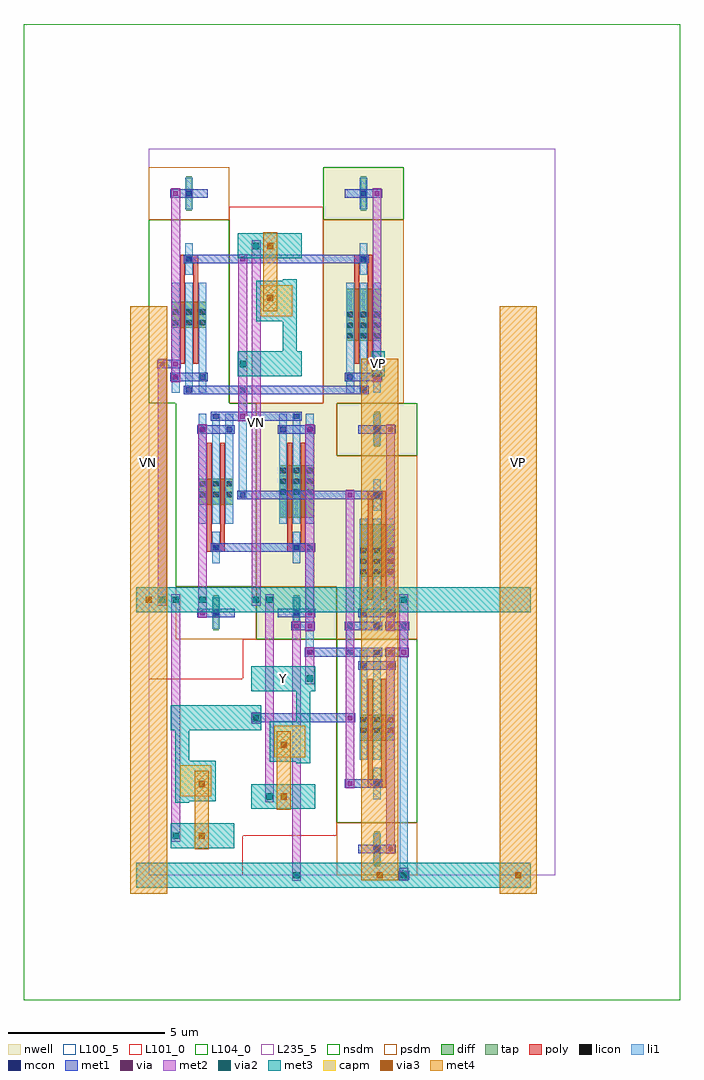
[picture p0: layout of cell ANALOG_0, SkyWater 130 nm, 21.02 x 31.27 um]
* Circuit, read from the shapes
.subckt ANALOG_0 VN VP Y
XM1 n1 n2 VN VN sky130_fd_pr__nfet_01v8 w=0.84 l=0.15 m=2
XM2 n2 Y VN VN sky130_fd_pr__nfet_01v8 w=0.84 l=0.15 m=2
XM3 Y n1 VN VN sky130_fd_pr__nfet_01v8 w=0.84 l=0.15 m=2
XM4 n2 Y VP VP sky130_fd_pr__pfet_01v8 w=1.68 l=0.15 m=2
XM5 n1 n2 VP VP sky130_fd_pr__pfet_01v8 w=1.68 l=0.15 m=2
XM6 Y n1 VP VP sky130_fd_pr__pfet_01v8 w=1.68 l=0.15 m=2
XC7 VN n1 sky130_fd_pr__cap_mim_m3_1 w=1 l=1
XC8 VN n2 sky130_fd_pr__cap_mim_m3_1 w=1 l=1
XC9 VN Y sky130_fd_pr__cap_mim_m3_1 w=1 l=1
.ends

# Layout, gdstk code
from math import pi, radians
import gdstk
lib = gdstk.Library(unit=1e-6, precision=1e-09)
def R(c, l, rs):  # rectangles x0, y0, x1, y1
    for r in rs: c.add(gdstk.rectangle(r[:2], r[2:], *l))
def A(c, l, x, y, w, h, nx, ny, dx, dy):  # array of equal rectangles
    R(c, l, [(x+i*dx, y+j*dy, x+i*dx+w, y+j*dy+h) for i in range(nx) for j in range(ny)])
def P(c, l, *ps):  # polygons
    for p in ps: c.add(gdstk.Polygon(p, *l))
nwell = (64, 20)
diff = (65, 20)
tap = (65, 44)
poly = (66, 20)
licon = (66, 44)
li1 = (67, 20)
mcon = (67, 44)
met1 = (68, 20)
via = (68, 44)
met2 = (69, 20)
via2 = (69, 44)
met3 = (70, 20)
via3 = (70, 44)
met4 = (71, 20)
capm = (89, 44)
nsdm = (93, 44)
psdm = (94, 20)
L100_5 = (100, 5)
L101_0 = (101, 0)
L104_0 = (104, 0)
L235_5 = (235, 5)

nmos_s_25628869_x1_y1_16 = lib.new_cell('NMOS_S_25628869_X1_Y1_1677518466_1677518466')
R(nmos_s_25628869_x1_y1_16, diff, [(0.735,2.415,1.845,3.255)])
R(nmos_s_25628869_x1_y1_16, tap, [(1.205,6.16,1.375,7.28)])
R(nmos_s_25628869_x1_y1_16, poly, [(1,1.26,1.15,4.62), (1.43,1.26,1.58,4.62), (1,4.485,1.58,4.755)])
A(nmos_s_25628869_x1_y1_16, licon, 0.775, 2.495, 0.17, 0.17, 3, 2, 0.43, 0.34)
R(nmos_s_25628869_x1_y1_16, licon, [(1.205,4.535,1.375,4.705), (1.205,6.635,1.375,6.805)])
A(nmos_s_25628869_x1_y1_16, li1, 0.735, 0.335, 0.25, 3.53, 3, 1, 0.43, 0)
R(nmos_s_25628869_x1_y1_16, li1, [(1.165,4.115,1.415,5.125), (1.165,6.215,1.415,7.225)])
R(nmos_s_25628869_x1_y1_16, mcon, [(1.205,0.335,1.375,0.505), (0.775,0.755,0.945,0.925), (1.635,0.755,1.805,0.925), (1.205,4.535,1.375,4.705), (1.205,6.635,1.375,6.805)])
R(nmos_s_25628869_x1_y1_16, met1, [(0.26,0.28,1.46,0.56), (0.69,0.7,1.89,0.98), (0.26,4.48,1.46,4.76), (0.69,6.58,1.89,6.86)])
R(nmos_s_25628869_x1_y1_16, via, [(1.645,0.765,1.795,0.915), (1.645,6.645,1.795,6.795)])
R(nmos_s_25628869_x1_y1_16, met2, [(1.58,0.68,1.86,6.88)])
R(nmos_s_25628869_x1_y1_16, nsdm, [(0,0,2.58,5.88)])
R(nmos_s_25628869_x1_y1_16, psdm, [(0,5.88,2.58,7.56)])
R(nmos_s_25628869_x1_y1_16, L100_5, [(0,0,2.58,7.56)])

pmos_s_89421238_x1_y1_16 = lib.new_cell('PMOS_S_89421238_X1_Y1_1677518467_1677518466')
R(pmos_s_89421238_x1_y1_16, nwell, [(0,0,2.58,7.56)])
R(pmos_s_89421238_x1_y1_16, diff, [(0.735,1.995,1.845,3.675)])
R(pmos_s_89421238_x1_y1_16, tap, [(1.205,6.16,1.375,7.28)])
R(pmos_s_89421238_x1_y1_16, poly, [(1,1.26,1.15,4.62), (1.43,1.26,1.58,4.62), (1,4.485,1.58,4.755)])
A(pmos_s_89421238_x1_y1_16, licon, 0.775, 2.075, 0.17, 0.17, 3, 3, 0.43, 0.34)
R(pmos_s_89421238_x1_y1_16, licon, [(1.205,4.535,1.375,4.705), (1.205,6.635,1.375,6.805)])
A(pmos_s_89421238_x1_y1_16, li1, 0.735, 0.335, 0.25, 3.53, 3, 1, 0.43, 0)
R(pmos_s_89421238_x1_y1_16, li1, [(1.165,4.115,1.415,5.125), (1.165,6.215,1.415,7.225)])
R(pmos_s_89421238_x1_y1_16, mcon, [(1.205,0.335,1.375,0.505), (0.775,0.755,0.945,0.925), (1.635,0.755,1.805,0.925), (1.205,4.535,1.375,4.705), (1.205,6.635,1.375,6.805)])
R(pmos_s_89421238_x1_y1_16, met1, [(0.26,0.28,1.46,0.56), (0.69,0.7,1.89,0.98), (0.26,4.48,1.46,4.76), (0.69,6.58,1.89,6.86)])
R(pmos_s_89421238_x1_y1_16, via, [(1.645,0.765,1.795,0.915), (1.645,6.645,1.795,6.795)])
R(pmos_s_89421238_x1_y1_16, met2, [(1.58,0.68,1.86,6.88)])
R(pmos_s_89421238_x1_y1_16, nsdm, [(0,5.88,2.58,7.56)])
R(pmos_s_89421238_x1_y1_16, psdm, [(0,0,2.58,5.88)])
R(pmos_s_89421238_x1_y1_16, L100_5, [(0,0,2.58,7.56)])

inv_21850877_pg0_0_0_167 = lib.new_cell('INV_21850877_PG0_0_0_1677518466')
R(inv_21850877_pg0_0_0_167, li1, [(0.305,7.055,0.555,7.225), (0.305,7.055,0.555,7.225), (0.305,7.14,0.555,7.98), (0.305,7.895,0.555,8.065), (0.305,7.895,0.555,8.065)])
R(inv_21850877_pg0_0_0_167, mcon, [(0.345,7.055,0.515,7.225), (0.345,7.055,0.515,7.225), (0.345,7.895,0.515,8.065), (0.345,7.895,0.515,8.065)])
R(inv_21850877_pg0_0_0_167, met1, [(0.27,2.8,0.59,3.08), (0.27,2.8,0.59,3.08), (0.26,7,0.6,7.28), (0.26,7,0.6,7.28), (0.26,7.84,0.6,8.12), (0.26,7.84,0.6,8.12), (0.27,12.04,0.59,12.32), (0.27,12.04,0.59,12.32)])
P(inv_21850877_pg0_0_0_167, met1, [(0,0),(0,0),(0,0),(0,0)],
  [(0,0),(0,0),(0,0),(0,0)],
  [(0,0),(0,0),(0,0),(0,0)],
  [(0,0),(0,0),(0,0),(0,0)])
R(inv_21850877_pg0_0_0_167, via, [(0.355,2.865,0.505,3.015), (0.355,2.865,0.505,3.015), (0.355,12.105,0.505,12.255), (0.355,12.105,0.505,12.255)])
R(inv_21850877_pg0_0_0_167, met2, [(0.29,2.78,0.57,3.1), (0.29,2.78,0.57,3.1), (0.29,2.94,0.57,12.18), (0.29,12.02,0.57,12.34), (0.29,12.02,0.57,12.34)])
P(inv_21850877_pg0_0_0_167, met2, [(0,0),(0,0),(0,0),(0,0)],
  [(0,0),(0,0),(0,0),(0,0)])
R(inv_21850877_pg0_0_0_167, L235_5, [(0,0,2.58,15.12)])
inv_21850877_pg0_0_0_167.add(gdstk.Reference(nmos_s_25628869_x1_y1_16, (0,7.56), x_reflection=True))
inv_21850877_pg0_0_0_167.add(gdstk.Reference(pmos_s_89421238_x1_y1_16, (0,7.56)))

cap_2t_9576091_167751846 = lib.new_cell('CAP_2T_9576091_1677518467')
R(cap_2t_9576091_167751846, met3, [(0.265,0.86,2.315,1.66), (1.71,2.32,2.16,4.84), (0.86,2.37,2.16,3.67), (0.265,4.64,2.315,5.44)])
R(cap_2t_9576091_167751846, via3, [(1.21,1.16,1.41,1.36), (1.21,2.82,1.41,3.02)])
R(cap_2t_9576091_167751846, met4, [(1.085,0.83,1.535,3.35)])
R(cap_2t_9576091_167751846, capm, [(1.01,2.52,2.01,3.52)])
R(cap_2t_9576091_167751846, L100_5, [(0,0,3.01,6.3)])
R(cap_2t_9576091_167751846, L101_0, [(0,0,3.01,6.3)])

c_nmos_s_25628869_x1_y1_16 = lib.new_cell('NMOS_S_25628869_X1_Y1_1677518468')
R(c_nmos_s_25628869_x1_y1_16, diff, [(0.735,2.415,1.845,3.255)])
R(c_nmos_s_25628869_x1_y1_16, tap, [(1.205,6.16,1.375,7.28)])
R(c_nmos_s_25628869_x1_y1_16, poly, [(1,1.26,1.15,4.62), (1.43,1.26,1.58,4.62), (1,4.485,1.58,4.755)])
A(c_nmos_s_25628869_x1_y1_16, licon, 0.775, 2.495, 0.17, 0.17, 3, 2, 0.43, 0.34)
R(c_nmos_s_25628869_x1_y1_16, licon, [(1.205,4.535,1.375,4.705), (1.205,6.635,1.375,6.805)])
A(c_nmos_s_25628869_x1_y1_16, li1, 0.735, 0.335, 0.25, 3.53, 3, 1, 0.43, 0)
R(c_nmos_s_25628869_x1_y1_16, li1, [(1.165,4.115,1.415,5.125), (1.165,6.215,1.415,7.225)])
R(c_nmos_s_25628869_x1_y1_16, mcon, [(1.205,0.335,1.375,0.505), (0.775,0.755,0.945,0.925), (1.635,0.755,1.805,0.925), (1.205,4.535,1.375,4.705), (1.205,6.635,1.375,6.805)])
R(c_nmos_s_25628869_x1_y1_16, met1, [(0.26,0.28,1.46,0.56), (0.69,0.7,1.89,0.98), (0.26,4.48,1.46,4.76), (0.69,6.58,1.89,6.86)])
R(c_nmos_s_25628869_x1_y1_16, via, [(1.645,0.765,1.795,0.915), (1.645,6.645,1.795,6.795)])
R(c_nmos_s_25628869_x1_y1_16, met2, [(1.58,0.68,1.86,6.88)])
R(c_nmos_s_25628869_x1_y1_16, nsdm, [(0,0,2.58,5.88)])
R(c_nmos_s_25628869_x1_y1_16, psdm, [(0,5.88,2.58,7.56)])
R(c_nmos_s_25628869_x1_y1_16, L100_5, [(0,0,2.58,7.56)])

c_pmos_s_89421238_x1_y1_16 = lib.new_cell('PMOS_S_89421238_X1_Y1_1677518469')
R(c_pmos_s_89421238_x1_y1_16, nwell, [(0,0,2.58,7.56)])
R(c_pmos_s_89421238_x1_y1_16, diff, [(0.735,1.995,1.845,3.675)])
R(c_pmos_s_89421238_x1_y1_16, tap, [(1.205,6.16,1.375,7.28)])
R(c_pmos_s_89421238_x1_y1_16, poly, [(1,1.26,1.15,4.62), (1.43,1.26,1.58,4.62), (1,4.485,1.58,4.755)])
A(c_pmos_s_89421238_x1_y1_16, licon, 0.775, 2.075, 0.17, 0.17, 3, 3, 0.43, 0.34)
R(c_pmos_s_89421238_x1_y1_16, licon, [(1.205,4.535,1.375,4.705), (1.205,6.635,1.375,6.805)])
A(c_pmos_s_89421238_x1_y1_16, li1, 0.735, 0.335, 0.25, 3.53, 3, 1, 0.43, 0)
R(c_pmos_s_89421238_x1_y1_16, li1, [(1.165,4.115,1.415,5.125), (1.165,6.215,1.415,7.225)])
R(c_pmos_s_89421238_x1_y1_16, mcon, [(1.205,0.335,1.375,0.505), (0.775,0.755,0.945,0.925), (1.635,0.755,1.805,0.925), (1.205,4.535,1.375,4.705), (1.205,6.635,1.375,6.805)])
R(c_pmos_s_89421238_x1_y1_16, met1, [(0.26,0.28,1.46,0.56), (0.69,0.7,1.89,0.98), (0.26,4.48,1.46,4.76), (0.69,6.58,1.89,6.86)])
R(c_pmos_s_89421238_x1_y1_16, via, [(1.645,0.765,1.795,0.915), (1.645,6.645,1.795,6.795)])
R(c_pmos_s_89421238_x1_y1_16, met2, [(1.58,0.68,1.86,6.88)])
R(c_pmos_s_89421238_x1_y1_16, nsdm, [(0,5.88,2.58,7.56)])
R(c_pmos_s_89421238_x1_y1_16, psdm, [(0,0,2.58,5.88)])
R(c_pmos_s_89421238_x1_y1_16, L100_5, [(0,0,2.58,7.56)])

analog_0 = lib.new_cell('ANALOG_0')
R(analog_0, li1, [(8.045,-0.085,8.295,0.085), (8.045,0,8.295,7.98), (5.035,7.055,5.285,7.225), (5.035,7.055,5.285,7.225), (5.035,7.055,5.285,7.225), (5.035,7.055,5.285,7.225), (5.035,7.14,5.285,10.5), (8.045,7.895,8.295,8.065), (8.045,7.895,8.295,8.065), (5.035,10.415,5.285,10.585), (5.035,10.415,5.285,10.585), (5.035,10.415,5.285,10.585), (5.035,10.415,5.285,10.585), (2.885,12.095,3.135,12.265), (2.885,12.095,3.135,12.265), (2.885,12.095,3.135,12.265), (2.885,12.095,3.135,12.265), (2.885,12.18,3.135,15.54), (2.885,15.455,3.135,15.625), (2.885,15.455,3.135,15.625), (2.885,15.455,3.135,15.625), (2.885,15.455,3.135,15.625)])
P(analog_0, li1, [(0,0),(0,0),(0,0),(0,0)])
R(analog_0, mcon, [(8.085,-0.085,8.255,0.085), (5.075,7.055,5.245,7.225), (5.075,7.055,5.245,7.225), (5.075,7.055,5.245,7.225), (5.075,7.055,5.245,7.225), (8.085,7.895,8.255,8.065), (8.085,7.895,8.255,8.065), (5.075,10.415,5.245,10.585), (5.075,10.415,5.245,10.585), (5.075,10.415,5.245,10.585), (5.075,10.415,5.245,10.585), (2.925,12.095,3.095,12.265), (2.925,12.095,3.095,12.265), (2.925,12.095,3.095,12.265), (2.925,12.095,3.095,12.265), (2.925,15.455,3.095,15.625), (2.925,15.455,3.095,15.625), (2.925,15.455,3.095,15.625), (2.925,15.455,3.095,15.625)])
R(analog_0, met1, [(8,-0.14,8.34,0.14), (8.01,-0.14,8.33,0.14), (8.021,-0.14,8.319,0.14), (3.28,4.9,3.6,5.18), (3.44,4.9,6.45,5.18), (6.29,4.9,6.61,5.18), (6.29,4.9,6.61,5.18), (6.29,4.9,6.61,5.18), (6.29,4.9,6.61,5.18), (6.29,4.9,6.61,5.18), (6.29,4.9,6.61,5.18), (4.99,7,5.33,7.28), (4.99,7,5.33,7.28), (4.99,7,5.33,7.28), (4.99,7,5.33,7.28), (5,7,5.32,7.28), (5,7,5.32,7.28), (5,7,5.32,7.28), (5,7,5.32,7.28), (5,7,5.32,7.28), (5,7,5.32,7.28), (5.16,7,6.45,7.28), (7.58,7,7.9,7.28), (7.58,7,7.9,7.28), (7.74,7,8.17,7.28), (8.01,7,8.33,7.28), (8.01,7,8.33,7.28), (4.57,7.84,4.89,8.12), (4.57,7.84,4.89,8.12), (4.57,7.84,4.89,8.12), (4.73,7.84,5.16,8.12), (5,7.84,5.32,8.12), (5,7.84,5.32,8.12), (5,7.84,5.32,8.12), (7.58,7.84,7.9,8.12), (7.58,7.84,7.9,8.12), (7.74,7.84,8.17,8.12), (8,7.84,8.34,8.12), (8,7.84,8.34,8.12), (3.01,10.36,3.87,10.64), (4.73,10.36,5.16,10.64), (4.99,10.36,5.33,10.64), (4.99,10.36,5.33,10.64), (4.99,10.36,5.33,10.64), (4.99,10.36,5.33,10.64), (2.84,12.04,3.18,12.32), (2.84,12.04,3.18,12.32), (2.84,12.04,3.18,12.32), (2.84,12.04,3.18,12.32), (3.01,12.04,6.45,12.32), (2.85,14.56,3.17,14.84), (2.85,14.56,3.17,14.84), (2.85,14.56,3.17,14.84), (2.85,14.56,3.17,14.84), (2.85,14.56,3.17,14.84), (2.85,14.56,3.17,14.84), (3.01,14.56,3.87,14.84), (2.15,15.4,3.01,15.68), (2.84,15.4,3.18,15.68), (2.84,15.4,3.18,15.68), (2.84,15.4,3.18,15.68), (2.84,15.4,3.18,15.68), (3.01,15.4,6.02,15.68), (0.27,16.24,0.59,16.52), (0.27,16.24,0.59,16.52), (0.27,16.24,0.59,16.52), (0.43,16.24,0.86,16.52), (0.7,16.24,1.02,16.52), (0.7,16.24,1.02,16.52), (0.7,16.24,1.02,16.52), (2.15,19.6,3.01,19.88), (2.85,19.6,3.17,19.88), (2.85,19.6,3.17,19.88), (2.85,19.6,3.17,19.88), (2.85,19.6,3.17,19.88), (3.01,19.6,6.02,19.88)])
P(analog_0, met1, [(0,0),(0,0),(0,0),(0,0)],
  [(0,0),(0,0),(0,0),(0,0)],
  [(0,0),(0,0),(0,0),(0,0)],
  [(0,0),(0,0),(0,0),(0,0)],
  [(0,0),(0,0),(0,0),(0,0)],
  [(0,0),(0,0),(0,0),(0,0)],
  [(0,0),(0,0),(0,0),(0,0)],
  [(0,0),(0,0),(0,0),(0,0)],
  [(0,0),(0,0),(0,0),(0,0)],
  [(0,0),(0,0),(0,0),(0,0)],
  [(0,0),(0,0),(0,0),(0,0)],
  [(0,0),(0,0),(0,0),(0,0)],
  [(0,0),(0,0),(0,0),(0,0)],
  [(0,0),(0,0),(0,0),(0,0)],
  [(0,0),(0,0),(0,0),(0,0)],
  [(0,0),(0,0),(0,0),(0,0)])
R(analog_0, via, [(8.095,-0.075,8.245,0.075), (3.365,4.965,3.515,5.115), (6.375,4.965,6.525,5.115), (6.375,4.965,6.525,5.115), (6.375,4.965,6.525,5.115), (6.375,4.965,6.525,5.115), (6.375,4.965,6.525,5.115), (6.375,4.965,6.525,5.115), (5.085,7.065,5.235,7.215), (5.085,7.065,5.235,7.215), (5.085,7.065,5.235,7.215), (5.085,7.065,5.235,7.215), (5.085,7.065,5.235,7.215), (5.085,7.065,5.235,7.215), (7.665,7.065,7.815,7.215), (7.665,7.065,7.815,7.215), (8.095,7.065,8.245,7.215), (8.095,7.065,8.245,7.215), (4.655,7.905,4.805,8.055), (4.655,7.905,4.805,8.055), (4.655,7.905,4.805,8.055), (5.085,7.905,5.235,8.055), (5.085,7.905,5.235,8.055), (5.085,7.905,5.235,8.055), (7.665,7.905,7.815,8.055), (7.665,7.905,7.815,8.055), (2.935,14.625,3.085,14.775), (2.935,14.625,3.085,14.775), (2.935,14.625,3.085,14.775), (2.935,14.625,3.085,14.775), (2.935,14.625,3.085,14.775), (2.935,14.625,3.085,14.775), (0.355,16.305,0.505,16.455), (0.355,16.305,0.505,16.455), (0.355,16.305,0.505,16.455), (0.785,16.305,0.935,16.455), (0.785,16.305,0.935,16.455), (0.785,16.305,0.935,16.455), (2.935,19.665,3.085,19.815), (2.935,19.665,3.085,19.815), (2.935,19.665,3.085,19.815), (2.935,19.665,3.085,19.815)])
R(analog_0, met2, [(4.59,-0.185,4.87,0.185), (4.59,-0.185,4.87,0.185), (4.59,-0.185,4.87,0.185), (8.03,-0.185,8.31,0.185), (8.03,-0.185,8.31,0.185), (8.03,-0.16,8.31,0.16), (4.59,0,4.87,7.98), (8.03,0,8.31,0.242), (0.72,1.075,1,1.445), (0.72,1.075,1,1.445), (0.72,1.075,1,1.445), (0.72,1.075,1,1.445), (0.72,1.075,1,1.445), (0.72,1.075,1,1.445), (0.72,1.26,1,8.82), (3.73,2.335,4.01,2.705), (3.73,2.335,4.01,2.705), (3.73,2.335,4.01,2.705), (3.73,2.335,4.01,2.705), (3.73,2.335,4.01,2.705), (3.73,2.52,4.01,8.82), (3.3,4.855,3.58,5.225), (3.3,4.88,3.58,5.2), (6.31,4.88,6.59,5.2), (6.31,4.88,6.59,5.2), (6.31,4.88,6.59,5.2), (6.31,4.88,6.59,5.2), (6.31,4.88,6.59,5.2), (6.31,4.88,6.59,5.2), (3.3,4.919,3.58,5.161), (5.02,6.115,5.3,6.485), (5.02,6.115,5.3,6.485), (5.02,6.115,5.3,6.485), (5.02,6.115,5.3,6.485), (5.02,6.115,5.3,6.485), (5.02,6.115,5.3,6.485), (5.02,6.3,5.3,7.14), (7.6,6.72,7.88,7.14), (5.02,6.98,5.3,7.3), (5.02,6.98,5.3,7.3), (5.02,6.98,5.3,7.3), (5.02,6.98,5.3,7.3), (5.02,6.98,5.3,7.3), (5.02,6.98,5.3,7.3), (7.6,6.98,7.88,7.3), (7.6,6.98,7.88,7.3), (8.03,6.98,8.31,7.3), (8.03,6.98,8.31,7.3), (8.03,7.14,8.31,8.82), (4.59,7.82,4.87,8.14), (4.59,7.82,4.87,8.14), (4.59,7.82,4.87,8.14), (5.02,7.82,5.3,8.14), (5.02,7.82,5.3,8.14), (5.02,7.82,5.3,8.14), (7.6,7.82,7.88,8.14), (7.6,7.82,7.88,8.14), (5.02,7.98,5.3,8.4), (7.6,7.98,7.88,8.4), (0.29,8.635,0.57,9.005), (0.29,8.635,0.57,9.005), (0.29,8.635,0.57,9.005), (0.72,8.635,1,9.005), (0.72,8.635,1,9.005), (0.72,8.635,1,9.005), (0.72,8.635,1,9.005), (0.72,8.635,1,9.005), (0.72,8.635,1,9.005), (1.58,8.635,1.86,9.005), (1.58,8.635,1.86,9.005), (1.58,8.635,1.86,9.005), (1.58,8.635,1.86,9.005), (3.3,8.635,3.58,9.005), (3.3,8.635,3.58,9.005), (3.3,8.635,3.58,9.005), (3.3,8.635,3.58,9.005), (3.3,8.635,3.58,9.005), (3.3,8.635,3.58,9.005), (3.3,8.635,3.58,9.005), (3.73,8.635,4.01,9.005), (3.73,8.635,4.01,9.005), (3.73,8.635,4.01,9.005), (3.73,8.635,4.01,9.005), (3.73,8.635,4.01,9.005), (8.03,8.635,8.31,9.005), (8.03,8.635,8.31,9.005), (0.29,8.82,0.57,16.38), (3.3,8.82,3.58,20.16), (2.87,14.54,3.15,14.86), (2.87,14.54,3.15,14.86), (2.87,14.54,3.15,14.86), (2.87,14.54,3.15,14.86), (2.87,14.54,3.15,14.86), (2.87,14.54,3.15,14.86), (2.87,14.7,3.15,16.38), (2.87,16.195,3.15,16.565), (2.87,16.195,3.15,16.565), (2.87,16.195,3.15,16.565), (2.87,16.195,3.15,16.565), (2.87,16.195,3.15,16.565), (2.87,16.195,3.15,16.565), (7.17,16.195,7.45,16.565), (0.29,16.22,0.57,16.54), (0.29,16.22,0.57,16.54), (0.29,16.22,0.57,16.54), (0.72,16.22,1,16.54), (0.72,16.22,1,16.54), (0.72,16.22,1,16.54), (2.87,16.38,3.15,19.74), (2.87,19.58,3.15,19.9), (2.87,19.58,3.15,19.9), (2.87,19.58,3.15,19.9), (2.87,19.58,3.15,19.9), (3.3,19.975,3.58,20.345), (3.3,19.975,3.58,20.345), (3.3,19.975,3.58,20.345), (3.3,19.975,3.58,20.345), (3.3,19.975,3.58,20.345), (3.3,19.975,3.58,20.345), (3.3,19.975,3.58,20.345)])
P(analog_0, met2, [(0,0),(0,0),(0,0),(0,0)],
  [(0,0),(0,0),(0,0),(0,0)],
  [(0,0),(0,0),(0,0),(0,0)],
  [(0,0),(0,0),(0,0),(0,0)],
  [(0,0),(0,0),(0,0),(0,0)])
R(analog_0, via2, [(4.63,-0.1,4.83,0.1), (4.63,-0.1,4.83,0.1), (4.63,-0.1,4.83,0.1), (8.07,-0.1,8.27,0.1), (8.07,-0.1,8.27,0.1), (0.76,1.16,0.96,1.36), (0.76,1.16,0.96,1.36), (0.76,1.16,0.96,1.36), (0.76,1.16,0.96,1.36), (0.76,1.16,0.96,1.36), (0.76,1.16,0.96,1.36), (3.77,2.42,3.97,2.62), (3.77,2.42,3.97,2.62), (3.77,2.42,3.97,2.62), (3.77,2.42,3.97,2.62), (3.77,2.42,3.97,2.62), (3.34,4.94,3.54,5.14), (5.06,6.2,5.26,6.4), (5.06,6.2,5.26,6.4), (5.06,6.2,5.26,6.4), (5.06,6.2,5.26,6.4), (5.06,6.2,5.26,6.4), (5.06,6.2,5.26,6.4), (0.33,8.72,0.53,8.92), (0.33,8.72,0.53,8.92), (0.33,8.72,0.53,8.92), (0.76,8.72,0.96,8.92), (0.76,8.72,0.96,8.92), (0.76,8.72,0.96,8.92), (0.76,8.72,0.96,8.92), (0.76,8.72,0.96,8.92), (0.76,8.72,0.96,8.92), (1.62,8.72,1.82,8.92), (1.62,8.72,1.82,8.92), (1.62,8.72,1.82,8.92), (1.62,8.72,1.82,8.92), (3.34,8.72,3.54,8.92), (3.34,8.72,3.54,8.92), (3.34,8.72,3.54,8.92), (3.34,8.72,3.54,8.92), (3.34,8.72,3.54,8.92), (3.34,8.72,3.54,8.92), (3.34,8.72,3.54,8.92), (3.77,8.72,3.97,8.92), (3.77,8.72,3.97,8.92), (3.77,8.72,3.97,8.92), (3.77,8.72,3.97,8.92), (3.77,8.72,3.97,8.92), (8.07,8.72,8.27,8.92), (8.07,8.72,8.27,8.92), (2.91,16.28,3.11,16.48), (2.91,16.28,3.11,16.48), (2.91,16.28,3.11,16.48), (2.91,16.28,3.11,16.48), (2.91,16.28,3.11,16.48), (2.91,16.28,3.11,16.48), (7.21,16.28,7.41,16.48), (3.34,20.06,3.54,20.26), (3.34,20.06,3.54,20.26), (3.34,20.06,3.54,20.26), (3.34,20.06,3.54,20.26), (3.34,20.06,3.54,20.26), (3.34,20.06,3.54,20.26), (3.34,20.06,3.54,20.26)])
A(analog_0, met3, -0.4, -0.4, 4.24, 0.8, 3, 2, 3.44, 8.82)
R(analog_0, met3, [(4.565,-0.4,4.895,0.4), (4.565,-0.4,4.895,0.4), (4.565,-0.4,4.895,0.4), (7.235,-0.4,7.565,0.4), (7.235,-0.4,7.565,0.4), (7.235,-0.4,7.565,0.4), (7.235,-0.4,7.565,0.4), (8.005,-0.4,8.335,0.4), (8.005,-0.4,8.335,0.4), (9.92,-0.4,12.24,0.4), (11.675,-0.4,12.005,0.4), (0.695,0.86,1.025,1.66), (0.695,0.86,1.025,1.66), (0.695,0.86,1.025,1.66), (0.695,0.86,1.025,1.66), (0.695,0.86,1.025,1.66), (0.695,0.86,1.025,1.66), (3.705,2.12,4.035,2.92), (3.705,2.12,4.035,2.92), (3.705,2.12,4.035,2.92), (3.705,2.12,4.035,2.92), (3.705,2.12,4.035,2.92), (2.58,4.64,3.44,5.44), (3.275,4.64,3.605,5.44), (4.995,5.9,5.325,6.7), (4.995,5.9,5.325,6.7), (4.995,5.9,5.325,6.7), (4.995,5.9,5.325,6.7), (4.995,5.9,5.325,6.7), (4.995,5.9,5.325,6.7), (-0.165,8.42,0.165,9.22), (0.265,8.42,0.595,9.22), (0.265,8.42,0.595,9.22), (0.265,8.42,0.595,9.22), (0.695,8.42,1.025,9.22), (0.695,8.42,1.025,9.22), (0.695,8.42,1.025,9.22), (0.695,8.42,1.025,9.22), (0.695,8.42,1.025,9.22), (0.695,8.42,1.025,9.22), (1.555,8.42,1.885,9.22), (1.555,8.42,1.885,9.22), (1.555,8.42,1.885,9.22), (1.555,8.42,1.885,9.22), (3.275,8.42,3.605,9.22), (3.275,8.42,3.605,9.22), (3.275,8.42,3.605,9.22), (3.275,8.42,3.605,9.22), (3.275,8.42,3.605,9.22), (3.275,8.42,3.605,9.22), (3.275,8.42,3.605,9.22), (3.705,8.42,4.035,9.22), (3.705,8.42,4.035,9.22), (3.705,8.42,4.035,9.22), (3.705,8.42,4.035,9.22), (3.705,8.42,4.035,9.22), (8.005,8.42,8.335,9.22), (8.005,8.42,8.335,9.22), (9.92,8.42,12.24,9.22), (2.845,15.98,3.175,16.78), (2.845,15.98,3.175,16.78), (2.845,15.98,3.175,16.78), (2.845,15.98,3.175,16.78), (2.845,15.98,3.175,16.78), (2.845,15.98,3.175,16.78), (7.145,15.98,7.475,16.78), (7.205,15.98,7.505,16.78), (7.235,15.98,7.565,16.78), (3.275,19.76,3.605,20.56), (3.275,19.76,3.605,20.56), (3.275,19.76,3.605,20.56), (3.275,19.76,3.605,20.56), (3.275,19.76,3.605,20.56), (3.275,19.76,3.605,20.56), (3.275,19.76,3.605,20.56)])
P(analog_0, met3, [(0,0),(0,0),(0,0),(0,0)],
  [(0,0),(0,0),(0,0),(0,0)],
  [(0,0),(0,0),(0,0),(0,0)],
  [(0,0),(0,0),(0,0),(0,0)],
  [(0,0),(0,0),(0,0),(0,0)],
  [(0,0),(0,0),(0,0),(0,0)],
  [(0,0),(0,0),(0,0),(0,0)])
R(analog_0, via3, [(7.3,-0.1,7.5,0.1), (7.3,-0.1,7.5,0.1), (7.3,-0.1,7.5,0.1), (7.3,-0.1,7.5,0.1), (11.74,-0.1,11.94,0.1), (-0.1,8.72,0.1,8.92), (7.3,16.28,7.5,16.48)])
R(analog_0, met4, [(-0.59,-0.59,0.59,9.41), (11.25,-0.59,12.43,9.41), (6.81,-0.165,7.99,0.165), (6.81,-0.165,7.99,0.165), (6.81,-0.165,7.99,0.165), (6.81,-0.165,7.99,0.165), (11.25,-0.165,12.43,0.165), (6.81,0,7.99,16.38), (-0.59,8.23,0.59,18.23), (11.25,8.23,12.43,18.23), (-0.59,8.655,0.59,8.985), (6.81,16.215,7.99,16.545)])
R(analog_0, L104_0, [(-4,-4,17.02,27.27)])
R(analog_0, L235_5, [(0,0,13.02,23.27)])
analog_0.add(gdstk.Reference(inv_21850877_pg0_0_0_167, (6.02,0)))
analog_0.add(gdstk.Reference(cap_2t_9576091_167751846, (2.58,21.42), x_reflection=True))
analog_0.add(gdstk.Reference(cap_2t_9576091_167751846, (3.01,0), rotation=pi, x_reflection=True))
analog_0.add(gdstk.Reference(cap_2t_9576091_167751846, (3.01,1.26)))
analog_0.add(gdstk.Reference(c_nmos_s_25628869_x1_y1_16, (3.44,15.12), rotation=pi))
analog_0.add(gdstk.Reference(c_nmos_s_25628869_x1_y1_16, (2.58,15.12), rotation=pi, x_reflection=True))
analog_0.add(gdstk.Reference(c_pmos_s_89421238_x1_y1_16, (5.59,15.12)))
analog_0.add(gdstk.Reference(c_pmos_s_89421238_x1_y1_16, (3.44,15.12), x_reflection=True))
analog_0.add(gdstk.Label('Y', (4.3,6.3), layer=70, texttype=5))
analog_0.add(gdstk.Label('VN', (0,13.23), layer=71, texttype=5))
analog_0.add(gdstk.Label('VN', (3.44,14.49), layer=69, texttype=5))
analog_0.add(gdstk.Label('VN', (0,13.23), layer=71, texttype=5))
analog_0.add(gdstk.Label('VN', (0,13.23), layer=71, texttype=5))
analog_0.add(gdstk.Label('VN', (0,13.23), layer=71, texttype=5))
analog_0.add(gdstk.Label('VN', (0,13.23), layer=71, texttype=5))
analog_0.add(gdstk.Label('VN', (0,13.23), layer=71, texttype=5))
analog_0.add(gdstk.Label('VN', (0,13.23), layer=71, texttype=5))
analog_0.add(gdstk.Label('VN', (0,13.23), layer=71, texttype=5))
analog_0.add(gdstk.Label('VN', (0,13.23), layer=71, texttype=5))
analog_0.add(gdstk.Label('VN', (0,13.23), layer=71, texttype=5))
analog_0.add(gdstk.Label('VN', (0,13.23), layer=71, texttype=5))
analog_0.add(gdstk.Label('VN', (0,13.23), layer=71, texttype=5))
analog_0.add(gdstk.Label('VN', (0,13.23), layer=71, texttype=5))
analog_0.add(gdstk.Label('VN', (0,13.23), layer=71, texttype=5))
analog_0.add(gdstk.Label('VN', (0,13.23), layer=71, texttype=5))
analog_0.add(gdstk.Label('VN', (0,13.23), layer=71, texttype=5))
analog_0.add(gdstk.Label('VN', (0,13.23), layer=71, texttype=5))
analog_0.add(gdstk.Label('VN', (0,13.23), layer=71, texttype=5))
analog_0.add(gdstk.Label('VN', (0,13.23), layer=71, texttype=5))
analog_0.add(gdstk.Label('VP', (11.84,13.23), layer=71, texttype=5))
analog_0.add(gdstk.Label('VP', (7.355,16.38), layer=70, texttype=5))
analog_0.add(gdstk.Label('VP', (11.84,13.23), layer=71, texttype=5))
analog_0.add(gdstk.Label('VP', (11.84,13.23), layer=71, texttype=5))
analog_0.add(gdstk.Label('VP', (11.84,13.23), layer=71, texttype=5))
analog_0.add(gdstk.Label('VP', (11.84,13.23), layer=71, texttype=5))
analog_0.add(gdstk.Label('VP', (11.84,13.23), layer=71, texttype=5))
analog_0.add(gdstk.Label('VP', (11.84,13.23), layer=71, texttype=5))
analog_0.add(gdstk.Label('VP', (11.84,13.23), layer=71, texttype=5))
analog_0.add(gdstk.Label('VP', (11.84,13.23), layer=71, texttype=5))
analog_0.add(gdstk.Label('VP', (11.84,13.23), layer=71, texttype=5))
analog_0.add(gdstk.Label('VP', (11.84,13.23), layer=71, texttype=5))
analog_0.add(gdstk.Label('VP', (11.84,13.23), layer=71, texttype=5))
analog_0.add(gdstk.Label('VP', (11.84,13.23), layer=71, texttype=5))
analog_0.add(gdstk.Label('VP', (11.84,13.23), layer=71, texttype=5))

lib.write_gds('ANALOG_0.gds')
